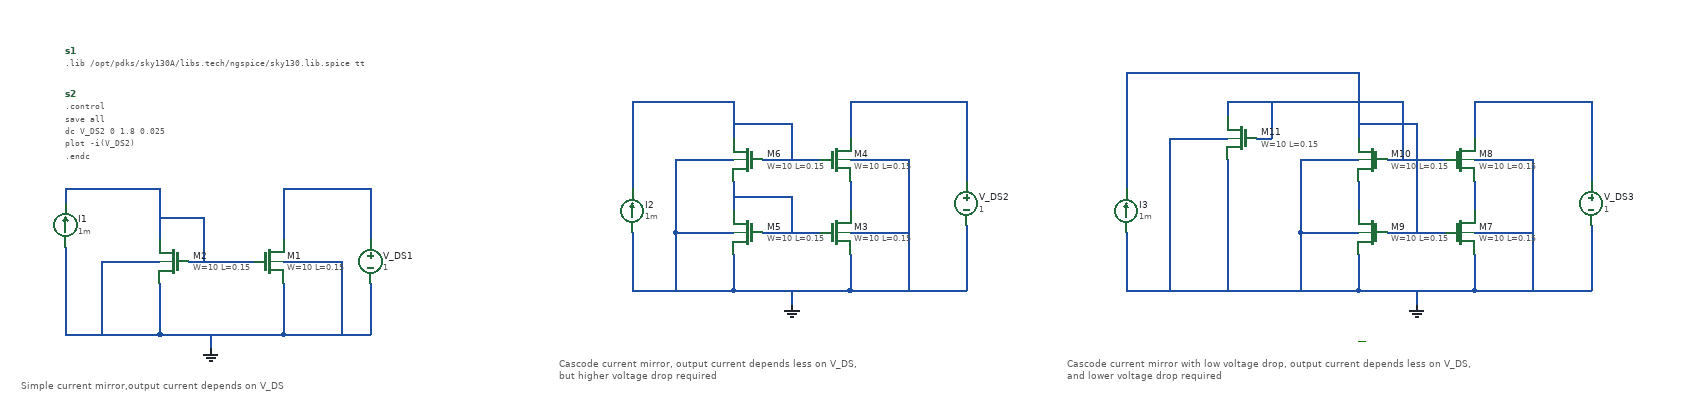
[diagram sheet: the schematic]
v {xschem version=3.1.0 file_version=1.2
}
G {}
K {}
V {}
S {}
E {}
L 4 1860 -90 1870 -90 {}
T {Simple current mirror,output current depends on V_DS} 20 -40 0 0 0.4 0.4 {}
T {Cascode current mirror, output current depends less on V_DS,
but higher voltage drop required} 760 -70 0 0 0.4 0.4 {}
T {Cascode current mirror with low voltage drop, output current depends less on V_DS,
and lower voltage drop required} 1460 -70 0 0 0.4 0.4 {}
N 210 -170 210 -100 {
lab=GND}
N 210 -100 370 -100 {
lab=GND}
N 380 -170 380 -100 {
lab=GND}
N 370 -100 380 -100 {
lab=GND}
N 280 -100 280 -80 {
lab=GND}
N 250 -200 340 -200 {
lab=#net1}
N 210 -300 210 -230 {
lab=#net1}
N 380 -300 380 -230 {
lab=#net2}
N 210 -260 260 -260 {
lab=#net1}
N 270 -240 270 -200 {
lab=#net1}
N 380 -300 490 -300 {
lab=#net2}
N 500 -300 500 -230 {
lab=#net2}
N 500 -170 500 -100 {
lab=GND}
N 380 -100 490 -100 {
lab=GND}
N 80 -300 210 -300 {
lab=#net1}
N 80 -100 210 -100 {
lab=GND}
N 490 -300 500 -300 {
lab=#net2}
N 490 -100 500 -100 {
lab=GND}
N 260 -260 270 -260 {
lab=#net1}
N 270 -260 270 -240 {
lab=#net1}
N 170 -200 210 -200 {
lab=GND}
N 130 -200 130 -100 {
lab=GND}
N 380 -200 400 -200 {
lab=GND}
N 400 -200 410 -200 {
lab=GND}
N 460 -200 460 -100 {
lab=GND}
N 410 -200 420 -200 {
lab=GND}
N 130 -200 170 -200 {
lab=GND}
N 420 -200 460 -200 {
lab=GND}
N 80 -300 80 -280 {
lab=#net1}
N 80 -220 80 -100 {
lab=GND}
N 1040 -340 1120 -340 {
lab=#net3}
N 1040 -240 1120 -240 {
lab=#net4}
N 1160 -310 1160 -270 {
lab=#net5}
N 1000 -210 1000 -160 {
lab=GND}
N 1000 -160 1160 -160 {
lab=GND}
N 1160 -210 1160 -160 {
lab=GND}
N 1080 -160 1080 -140 {
lab=GND}
N 1000 -310 1000 -270 {
lab=#net4}
N 860 -240 860 -160 {
lab=GND}
N 860 -160 1000 -160 {
lab=GND}
N 860 -400 860 -300 {
lab=#net3}
N 860 -420 1000 -420 {
lab=#net3}
N 1000 -400 1000 -370 {
lab=#net3}
N 860 -420 860 -400 {
lab=#net3}
N 1000 -420 1000 -400 {
lab=#net3}
N 1160 -420 1160 -370 {
lab=#net6}
N 1160 -420 1320 -420 {
lab=#net6}
N 1320 -420 1320 -310 {
lab=#net6}
N 1320 -250 1320 -160 {
lab=GND}
N 1160 -160 1320 -160 {
lab=GND}
N 1000 -290 1080 -290 {
lab=#net4}
N 1080 -290 1080 -240 {
lab=#net4}
N 1000 -390 1080 -390 {
lab=#net3}
N 1080 -390 1080 -340 {
lab=#net3}
N 920 -240 1000 -240 {
lab=GND}
N 920 -240 920 -160 {
lab=GND}
N 920 -340 1000 -340 {
lab=GND}
N 920 -340 920 -240 {
lab=GND}
N 1160 -340 1240 -340 {
lab=GND}
N 1240 -340 1240 -160 {
lab=GND}
N 1160 -240 1240 -240 {
lab=GND}
N 1900 -340 1980 -340 {
lab=#net7}
N 1900 -240 1980 -240 {
lab=#net8}
N 2020 -310 2020 -270 {
lab=#net9}
N 1860 -210 1860 -160 {
lab=GND}
N 1860 -160 2020 -160 {
lab=GND}
N 2020 -210 2020 -160 {
lab=GND}
N 1940 -160 1940 -140 {
lab=GND}
N 1860 -310 1860 -270 {
lab=#net10}
N 1540 -240 1540 -160 {
lab=#net11}
N 1720 -160 1860 -160 {
lab=GND}
N 1540 -400 1540 -300 {
lab=#net12}
N 1860 -400 1860 -370 {
lab=#net8}
N 1540 -420 1540 -400 {
lab=#net12}
N 2020 -420 2020 -370 {
lab=#net13}
N 2020 -420 2180 -420 {
lab=#net13}
N 2180 -420 2180 -310 {
lab=#net13}
N 2180 -250 2180 -160 {
lab=GND}
N 2020 -160 2180 -160 {
lab=GND}
N 1940 -290 1940 -240 {
lab=#net8}
N 1860 -390 1940 -390 {
lab=#net8}
N 1780 -240 1860 -240 {
lab=GND}
N 1780 -240 1780 -160 {
lab=GND}
N 1780 -340 1860 -340 {
lab=GND}
N 1780 -340 1780 -240 {
lab=GND}
N 2020 -340 2100 -340 {
lab=GND}
N 2100 -340 2100 -160 {
lab=GND}
N 2020 -240 2100 -240 {
lab=GND}
N 1940 -390 1940 -290 {
lab=#net8}
N 1680 -420 1680 -400 {}
N 1680 -420 1840 -420 {}
N 1860 -460 1860 -440 {}
N 1580 -460 1860 -460 {}
N 1540 -460 1540 -420 {}
N 1920 -420 1920 -340 {}
N 1840 -420 1920 -420 {}
N 1860 -440 1860 -400 {}
N 1720 -370 1740 -370 {}
N 1740 -420 1740 -370 {}
N 1680 -340 1680 -160 {}
N 1580 -160 1720 -160 {}
N 1600 -370 1680 -370 {}
N 1600 -370 1600 -160 {}
N 1540 -160 1580 -160 {}
N 1540 -460 1580 -460 {}
C {sky130_fd_pr/nfet_01v8.sym} 360 -200 0 0 {name=M1
L=0.15
W=10
nf=1 
mult=1
ad="'int((nf+1)/2) * W/nf * 0.29'" 
pd="'2*int((nf+1)/2) * (W/nf + 0.29)'"
as="'int((nf+2)/2) * W/nf * 0.29'" 
ps="'2*int((nf+2)/2) * (W/nf + 0.29)'"
nrd="'0.29 / W'" nrs="'0.29 / W'"
sa=0 sb=0 sd=0
model=nfet_01v8
spiceprefix=X
}
C {sky130_fd_pr/nfet_01v8.sym} 230 -200 0 1 {name=M2
L=0.15
W=10
nf=1 
mult=1
ad="'int((nf+1)/2) * W/nf * 0.29'" 
pd="'2*int((nf+1)/2) * (W/nf + 0.29)'"
as="'int((nf+2)/2) * W/nf * 0.29'" 
ps="'2*int((nf+2)/2) * (W/nf + 0.29)'"
nrd="'0.29 / W'" nrs="'0.29 / W'"
sa=0 sb=0 sd=0
model=nfet_01v8
spiceprefix=X
}
C {devices/gnd.sym} 280 -80 0 0 {name=l1 lab=GND}
C {devices/vsource.sym} 500 -200 0 0 {name=V_DS1 value=1}
C {devices/code_shown.sym} 80 -490 0 0 {name=s1 only_toplevel=false value=".lib /opt/pdks/sky130A/libs.tech/ngspice/sky130.lib.spice tt"}
C {devices/code_shown.sym} 80 -430 0 0 {name=s2 only_toplevel=false value=".control
save all
dc V_DS2 0 1.8 0.025
plot -i(V_DS2)
.endc"}
C {devices/isource.sym} 80 -250 2 0 {name=I1 value=1m}
C {sky130_fd_pr/nfet_01v8.sym} 1140 -240 0 0 {name=M3
L=0.15
W=10
nf=1 
mult=1
ad="'int((nf+1)/2) * W/nf * 0.29'" 
pd="'2*int((nf+1)/2) * (W/nf + 0.29)'"
as="'int((nf+2)/2) * W/nf * 0.29'" 
ps="'2*int((nf+2)/2) * (W/nf + 0.29)'"
nrd="'0.29 / W'" nrs="'0.29 / W'"
sa=0 sb=0 sd=0
model=nfet_01v8
spiceprefix=X
}
C {sky130_fd_pr/nfet_01v8.sym} 1140 -340 0 0 {name=M4
L=0.15
W=10
nf=1 
mult=1
ad="'int((nf+1)/2) * W/nf * 0.29'" 
pd="'2*int((nf+1)/2) * (W/nf + 0.29)'"
as="'int((nf+2)/2) * W/nf * 0.29'" 
ps="'2*int((nf+2)/2) * (W/nf + 0.29)'"
nrd="'0.29 / W'" nrs="'0.29 / W'"
sa=0 sb=0 sd=0
model=nfet_01v8
spiceprefix=X
}
C {sky130_fd_pr/nfet_01v8.sym} 1020 -240 0 1 {name=M5
L=0.15
W=10
nf=1 
mult=1
ad="'int((nf+1)/2) * W/nf * 0.29'" 
pd="'2*int((nf+1)/2) * (W/nf + 0.29)'"
as="'int((nf+2)/2) * W/nf * 0.29'" 
ps="'2*int((nf+2)/2) * (W/nf + 0.29)'"
nrd="'0.29 / W'" nrs="'0.29 / W'"
sa=0 sb=0 sd=0
model=nfet_01v8
spiceprefix=X
}
C {sky130_fd_pr/nfet_01v8.sym} 1020 -340 0 1 {name=M6
L=0.15
W=10
nf=1 
mult=1
ad="'int((nf+1)/2) * W/nf * 0.29'" 
pd="'2*int((nf+1)/2) * (W/nf + 0.29)'"
as="'int((nf+2)/2) * W/nf * 0.29'" 
ps="'2*int((nf+2)/2) * (W/nf + 0.29)'"
nrd="'0.29 / W'" nrs="'0.29 / W'"
sa=0 sb=0 sd=0
model=nfet_01v8
spiceprefix=X
}
C {devices/gnd.sym} 1080 -140 0 0 {name=l2 lab=GND}
C {devices/isource.sym} 860 -270 2 0 {name=I2 value=1m}
C {devices/vsource.sym} 1320 -280 0 0 {name=V_DS2 value=1}
C {sky130_fd_pr/nfet_01v8.sym} 2000 -240 0 0 {name=M7
L=0.15
W=10
nf=1 
mult=1
ad="'int((nf+1)/2) * W/nf * 0.29'" 
pd="'2*int((nf+1)/2) * (W/nf + 0.29)'"
as="'int((nf+2)/2) * W/nf * 0.29'" 
ps="'2*int((nf+2)/2) * (W/nf + 0.29)'"
nrd="'0.29 / W'" nrs="'0.29 / W'"
sa=0 sb=0 sd=0
model=nfet_01v8
spiceprefix=X
}
C {sky130_fd_pr/nfet_01v8.sym} 2000 -340 0 0 {name=M8
L=0.15
W=10
nf=1 
mult=1
ad="'int((nf+1)/2) * W/nf * 0.29'" 
pd="'2*int((nf+1)/2) * (W/nf + 0.29)'"
as="'int((nf+2)/2) * W/nf * 0.29'" 
ps="'2*int((nf+2)/2) * (W/nf + 0.29)'"
nrd="'0.29 / W'" nrs="'0.29 / W'"
sa=0 sb=0 sd=0
model=nfet_01v8
spiceprefix=X
}
C {sky130_fd_pr/nfet_01v8.sym} 1880 -240 0 1 {name=M9
L=0.15
W=10
nf=1 
mult=1
ad="'int((nf+1)/2) * W/nf * 0.29'" 
pd="'2*int((nf+1)/2) * (W/nf + 0.29)'"
as="'int((nf+2)/2) * W/nf * 0.29'" 
ps="'2*int((nf+2)/2) * (W/nf + 0.29)'"
nrd="'0.29 / W'" nrs="'0.29 / W'"
sa=0 sb=0 sd=0
model=nfet_01v8
spiceprefix=X
}
C {sky130_fd_pr/nfet_01v8.sym} 1880 -340 0 1 {name=M10
L=0.15
W=10
nf=1 
mult=1
ad="'int((nf+1)/2) * W/nf * 0.29'" 
pd="'2*int((nf+1)/2) * (W/nf + 0.29)'"
as="'int((nf+2)/2) * W/nf * 0.29'" 
ps="'2*int((nf+2)/2) * (W/nf + 0.29)'"
nrd="'0.29 / W'" nrs="'0.29 / W'"
sa=0 sb=0 sd=0
model=nfet_01v8
spiceprefix=X
}
C {devices/gnd.sym} 1940 -140 0 0 {name=l3 lab=GND}
C {devices/isource.sym} 1540 -270 2 0 {name=I3 value=1m}
C {devices/vsource.sym} 2180 -280 0 0 {name=V_DS3 value=1}
C {sky130_fd_pr/nfet_01v8.sym} 1700 -370 0 1 {name=M11
L=0.15
W=10
nf=1 
mult=1
ad="'int((nf+1)/2) * W/nf * 0.29'" 
pd="'2*int((nf+1)/2) * (W/nf + 0.29)'"
as="'int((nf+2)/2) * W/nf * 0.29'" 
ps="'2*int((nf+2)/2) * (W/nf + 0.29)'"
nrd="'0.29 / W'" nrs="'0.29 / W'"
sa=0 sb=0 sd=0
model=nfet_01v8
spiceprefix=X
}
